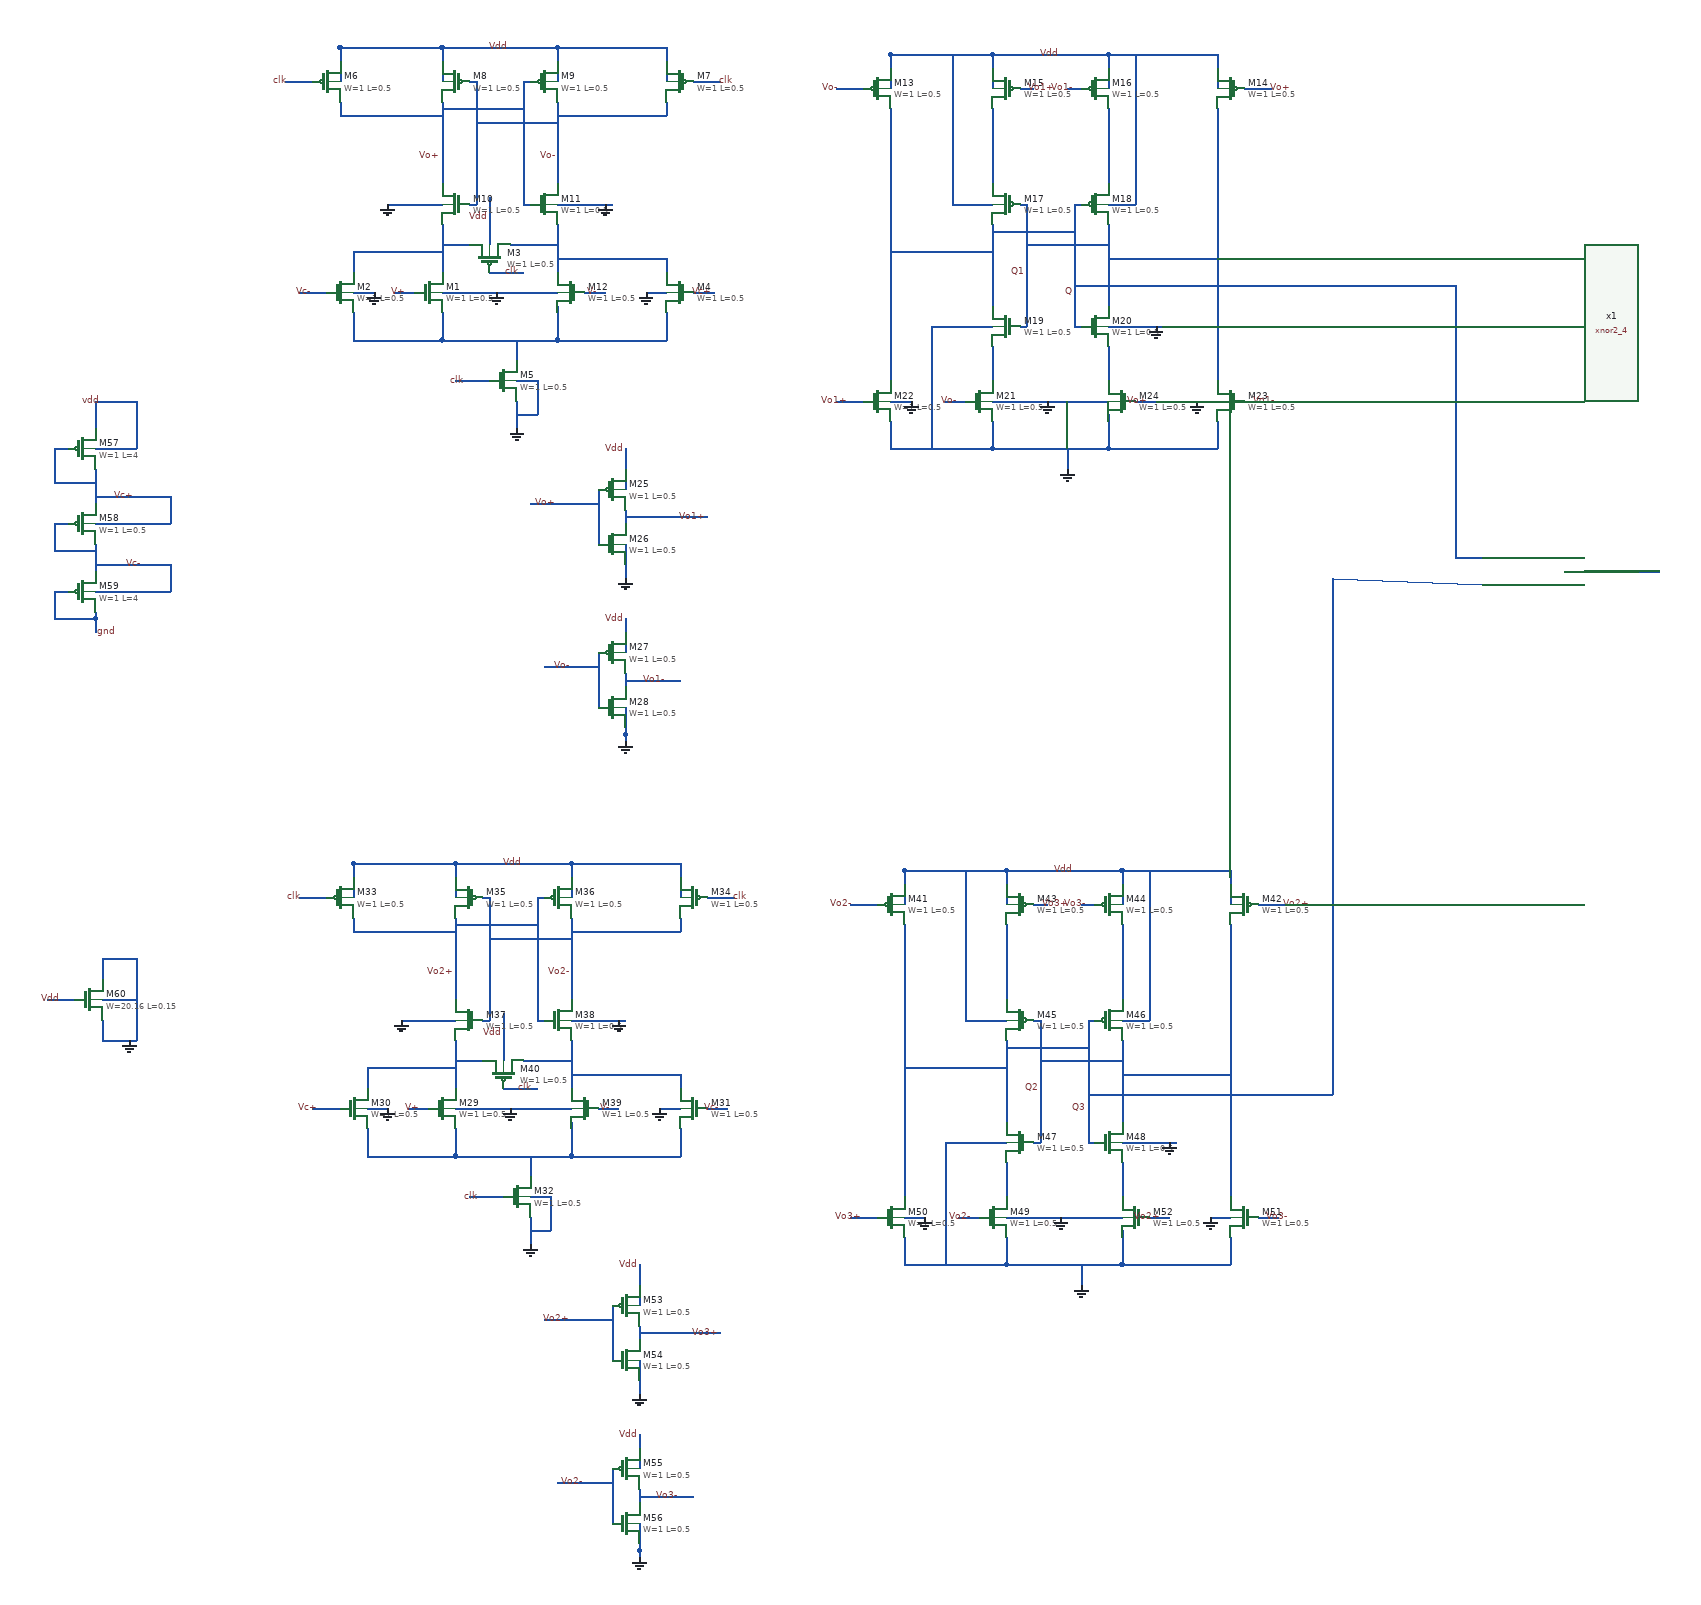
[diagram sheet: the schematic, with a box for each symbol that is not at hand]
v {xschem version=3.4.4 file_version=1.2
}
G {}
K {}
V {}
S {}
E {}
N -1410 -840 -1410 -720 {
lab=Vo+}
N -1240 -840 -1240 -730 {
lab=Vo-}
N -1240 -730 -1240 -720 {
lab=Vo-}
N -1410 -920 -1410 -900 {
lab=Vdd}
N -1410 -920 -1240 -920 {
lab=Vdd}
N -1240 -920 -1240 -900 {
lab=Vdd}
N -1370 -870 -1360 -870 {
lab=Vo-}
N -1360 -870 -1360 -690 {
lab=Vo-}
N -1370 -690 -1360 -690 {
lab=Vo-}
N -1290 -870 -1280 -870 {
lab=Vo+}
N -1290 -870 -1290 -690 {
lab=Vo+}
N -1290 -690 -1280 -690 {
lab=Vo+}
N -1560 -920 -1410 -920 {
lab=Vdd}
N -1560 -920 -1560 -900 {
lab=Vdd}
N -1240 -920 -1080 -920 {
lab=Vdd}
N -1080 -920 -1080 -900 {
lab=Vdd}
N -1560 -840 -1560 -820 {
lab=Vo+}
N -1560 -820 -1410 -820 {
lab=Vo+}
N -1080 -840 -1080 -820 {
lab=Vo-}
N -1240 -820 -1080 -820 {
lab=Vo-}
N -1410 -830 -1290 -830 {
lab=Vo+}
N -1360 -810 -1240 -810 {
lab=Vo-}
N -1410 -660 -1410 -590 {
lab=#net1}
N -1240 -660 -1240 -590 {
lab=#net2}
N -1410 -530 -1410 -490 {
lab=#net3}
N -1410 -490 -1240 -490 {
lab=#net3}
N -1240 -540 -1240 -490 {
lab=#net3}
N -1080 -530 -1080 -490 {
lab=#net3}
N -1240 -490 -1080 -490 {
lab=#net3}
N -1080 -610 -1080 -590 {
lab=#net2}
N -1240 -610 -1080 -610 {
lab=#net2}
N -1540 -530 -1540 -490 {
lab=#net3}
N -1540 -490 -1410 -490 {
lab=#net3}
N -1540 -620 -1540 -590 {
lab=#net1}
N -1540 -620 -1410 -620 {
lab=#net1}
N -1300 -490 -1300 -460 {
lab=#net3}
N -1390 -430 -1340 -430 {
lab=clk}
N -1300 -400 -1300 -360 {
lab=GND}
N -1410 -630 -1370 -630 {
lab=#net1}
N -1310 -630 -1240 -630 {
lab=#net2}
N -1620 -560 -1580 -560 {
lab=Vc-}
N -1480 -560 -1450 -560 {
lab=V+}
N -1200 -560 -1170 -560 {
lab=V-}
N -1040 -560 -1010 -560 {
lab=Vc+}
N -1040 -870 -1000 -870 {
lab=clk}
N -1640 -870 -1600 -870 {
lab=clk}
N -1410 -560 -1240 -560 {
lab=GND}
N -1110 -560 -1080 -560 {
lab=GND}
N -1540 -560 -1510 -560 {
lab=GND}
N -1560 -890 -1560 -870 {
lab=Vdd}
N -1410 -890 -1410 -870 {
lab=Vdd}
N -1240 -900 -1240 -880 {
lab=Vdd}
N -1240 -890 -1240 -870 {
lab=Vdd}
N -1080 -910 -1080 -870 {
lab=Vdd}
N -1410 -910 -1410 -870 {
lab=Vdd}
N -1560 -920 -1560 -870 {
lab=Vdd}
N -1240 -690 -1160 -690 {
lab=GND}
N -1490 -690 -1410 -690 {
lab=GND}
N -1340 -700 -1340 -630 {
lab=Vdd}
N -1340 -590 -1290 -590 {
lab=clk}
N -1300 -430 -1270 -430 {
lab=GND}
N -1270 -430 -1270 -380 {
lab=GND}
N -1300 -380 -1270 -380 {
lab=GND}
N -600 -910 -600 -890 {
lab=Vdd}
N -600 -910 -430 -910 {
lab=Vdd}
N -430 -910 -430 -890 {
lab=Vdd}
N -560 -860 -550 -860 {
lab=Vo1+}
N -480 -860 -470 -860 {
lab=Vo1-}
N -750 -910 -600 -910 {
lab=Vdd}
N -750 -910 -750 -890 {
lab=Vdd}
N -430 -910 -270 -910 {
lab=Vdd}
N -270 -910 -270 -890 {
lab=Vdd}
N -750 -830 -750 -810 {
lab=Q}
N -270 -830 -270 -810 {
lab=Q1}
N -230 -860 -190 -860 {
lab=Vo+}
N -830 -860 -790 -860 {
lab=Vo-}
N -750 -880 -750 -860 {
lab=Vdd}
N -600 -880 -600 -860 {
lab=Vdd}
N -430 -890 -430 -870 {
lab=Vdd}
N -430 -880 -430 -860 {
lab=Vdd}
N -270 -900 -270 -860 {
lab=Vdd}
N -600 -900 -600 -860 {
lab=Vdd}
N -750 -910 -750 -860 {
lab=Vdd}
N -430 -830 -430 -740 {
lab=#net4}
N -600 -660 -600 -540 {
lab=Q}
N -430 -660 -430 -550 {
lab=Q1}
N -430 -550 -430 -540 {
lab=Q1}
N -600 -740 -600 -720 {
lab=#net5}
N -430 -740 -430 -720 {
lab=#net4}
N -560 -690 -550 -690 {
lab=Q1}
N -550 -690 -550 -510 {
lab=Q1}
N -560 -510 -550 -510 {
lab=Q1}
N -480 -690 -470 -690 {
lab=Q}
N -480 -690 -480 -510 {
lab=Q}
N -480 -510 -470 -510 {
lab=Q}
N -600 -650 -480 -650 {
lab=Q}
N -550 -630 -430 -630 {
lab=Q1}
N -430 -510 -350 -510 {
lab=GND}
N -600 -830 -600 -740 {
lab=#net5}
N -600 -370 -600 -330 {
lab=GND}
N -600 -330 -430 -330 {
lab=GND}
N -430 -380 -430 -330 {
lab=GND}
N -270 -370 -270 -330 {
lab=GND}
N -430 -330 -270 -330 {
lab=GND}
N -270 -450 -270 -430 {
lab=Q1}
N -750 -370 -750 -330 {
lab=GND}
N -730 -330 -600 -330 {
lab=GND}
N -750 -460 -750 -430 {
lab=Q}
N -490 -330 -490 -300 {
lab=GND}
N -830 -400 -790 -400 {
lab=Vo1+}
N -670 -400 -640 -400 {
lab=Vo-}
N -390 -400 -360 -400 {
lab=Vo+}
N -230 -400 -200 -400 {
lab=Vo1-}
N -600 -400 -430 -400 {
lab=GND}
N -300 -400 -270 -400 {
lab=GND}
N -750 -400 -720 -400 {
lab=GND}
N -600 -480 -600 -430 {
lab=#net6}
N -430 -480 -430 -430 {
lab=#net7}
N -750 -810 -750 -460 {
lab=Q}
N -270 -810 -270 -460 {
lab=Q1}
N -270 -460 -270 -450 {
lab=Q1}
N -750 -330 -730 -330 {
lab=GND}
N -490 -860 -480 -860 {
lab=Vo1-}
N -550 -860 -540 -860 {
lab=Vo1+}
N -750 -620 -600 -620 {
lab=Q}
N -430 -610 -270 -610 {
lab=Q1}
N -1280 -250 -1200 -250 {
lab=Vo+}
N -1260 -10 -1180 -10 {
lab=Vo-}
N -1140 10 -1060 10 {
lab=Vo1-}
N -660 -690 -600 -690 {
lab=Vdd}
N -660 -910 -660 -690 {
lab=Vdd}
N -430 -690 -390 -690 {
lab=Vdd}
N -390 -910 -390 -690 {
lab=Vdd}
N -690 -510 -600 -510 {
lab=GND}
N -690 -510 -690 -330 {
lab=GND}
N -1140 -160 -1140 -140 {
lab=GND}
N -1180 -270 -1180 -190 {
lab=Vo+}
N -1200 -250 -1180 -250 {
lab=Vo+}
N -1140 -240 -1140 -220 {
lab=Vo1+}
N -1140 -230 -1020 -230 {
lab=Vo1+}
N -1140 -330 -1140 -300 {
lab=Vdd}
N -1140 -320 -1140 -270 {
lab=Vdd}
N -1140 -190 -1140 -150 {
lab=GND}
N -1180 -30 -1180 50 {
lab=Vo-}
N -1140 0 -1140 20 {
lab=Vo1-}
N -1140 90 -1140 100 {
lab=GND}
N -1140 80 -1140 90 {
lab=GND}
N -1140 50 -1140 90 {
lab=GND}
N -1140 -80 -1140 -60 {
lab=Vdd}
N -1140 -70 -1140 -30 {
lab=Vdd}
N -1390 360 -1390 480 {
lab=Vo2+}
N -1220 360 -1220 470 {
lab=Vo2-}
N -1220 470 -1220 480 {
lab=Vo2-}
N -1390 280 -1390 300 {
lab=Vdd}
N -1390 280 -1220 280 {
lab=Vdd}
N -1220 280 -1220 300 {
lab=Vdd}
N -1350 330 -1340 330 {
lab=Vo2-}
N -1340 330 -1340 510 {
lab=Vo2-}
N -1350 510 -1340 510 {
lab=Vo2-}
N -1270 330 -1260 330 {
lab=Vo2+}
N -1270 330 -1270 510 {
lab=Vo2+}
N -1270 510 -1260 510 {
lab=Vo2+}
N -1540 280 -1390 280 {
lab=Vdd}
N -1540 280 -1540 300 {
lab=Vdd}
N -1220 280 -1060 280 {
lab=Vdd}
N -1060 280 -1060 300 {
lab=Vdd}
N -1540 360 -1540 380 {
lab=Vo2+}
N -1540 380 -1390 380 {
lab=Vo2+}
N -1060 360 -1060 380 {
lab=Vo2-}
N -1220 380 -1060 380 {
lab=Vo2-}
N -1390 370 -1270 370 {
lab=Vo2+}
N -1340 390 -1220 390 {
lab=Vo2-}
N -1390 540 -1390 610 {
lab=#net8}
N -1220 540 -1220 610 {
lab=#net9}
N -1390 670 -1390 710 {
lab=#net10}
N -1390 710 -1220 710 {
lab=#net10}
N -1220 660 -1220 710 {
lab=#net10}
N -1060 670 -1060 710 {
lab=#net10}
N -1220 710 -1060 710 {
lab=#net10}
N -1060 590 -1060 610 {
lab=#net9}
N -1220 590 -1060 590 {
lab=#net9}
N -1520 670 -1520 710 {
lab=#net10}
N -1520 710 -1390 710 {
lab=#net10}
N -1520 580 -1520 610 {
lab=#net8}
N -1520 580 -1390 580 {
lab=#net8}
N -1280 710 -1280 740 {
lab=#net10}
N -1370 770 -1320 770 {
lab=clk}
N -1280 800 -1280 840 {
lab=GND}
N -1390 570 -1350 570 {
lab=#net8}
N -1290 570 -1220 570 {
lab=#net9}
N -1600 640 -1560 640 {
lab=Vc+}
N -1460 640 -1430 640 {
lab=V+}
N -1180 640 -1150 640 {
lab=V-}
N -1020 640 -990 640 {
lab=Vc-}
N -1020 330 -980 330 {
lab=clk}
N -1620 330 -1580 330 {
lab=clk}
N -1390 640 -1220 640 {
lab=GND}
N -1090 640 -1060 640 {
lab=GND}
N -1520 640 -1490 640 {
lab=GND}
N -1540 310 -1540 330 {
lab=Vdd}
N -1390 310 -1390 330 {
lab=Vdd}
N -1220 300 -1220 320 {
lab=Vdd}
N -1220 310 -1220 330 {
lab=Vdd}
N -1060 290 -1060 330 {
lab=Vdd}
N -1390 290 -1390 330 {
lab=Vdd}
N -1540 280 -1540 330 {
lab=Vdd}
N -1220 510 -1140 510 {
lab=GND}
N -1470 510 -1390 510 {
lab=GND}
N -1320 500 -1320 570 {
lab=Vdd}
N -1320 610 -1270 610 {
lab=clk}
N -1280 770 -1250 770 {
lab=GND}
N -1250 770 -1250 820 {
lab=GND}
N -1280 820 -1250 820 {
lab=GND}
N -580 290 -580 310 {
lab=Vdd}
N -580 290 -410 290 {
lab=Vdd}
N -410 290 -410 310 {
lab=Vdd}
N -540 340 -530 340 {
lab=Vo3+}
N -460 340 -450 340 {
lab=Vo3-}
N -730 290 -580 290 {
lab=Vdd}
N -730 290 -730 310 {
lab=Vdd}
N -410 290 -250 290 {
lab=Vdd}
N -250 290 -250 310 {
lab=Vdd}
N -730 370 -730 390 {
lab=Q3}
N -250 370 -250 390 {
lab=Q2}
N -210 340 -170 340 {
lab=Vo2+}
N -810 340 -770 340 {
lab=Vo2-}
N -730 320 -730 340 {
lab=Vdd}
N -580 320 -580 340 {
lab=Vdd}
N -410 310 -410 330 {
lab=Vdd}
N -410 320 -410 340 {
lab=Vdd}
N -250 300 -250 340 {
lab=Vdd}
N -580 300 -580 340 {
lab=Vdd}
N -730 290 -730 340 {
lab=Vdd}
N -410 370 -410 460 {
lab=#net11}
N -580 540 -580 660 {
lab=Q3}
N -410 540 -410 650 {
lab=Q2}
N -410 650 -410 660 {
lab=Q2}
N -580 460 -580 480 {
lab=#net12}
N -410 460 -410 480 {
lab=#net11}
N -540 510 -530 510 {
lab=Q2}
N -530 510 -530 690 {
lab=Q2}
N -540 690 -530 690 {
lab=Q2}
N -460 510 -450 510 {
lab=Q3}
N -460 510 -460 690 {
lab=Q3}
N -460 690 -450 690 {
lab=Q3}
N -580 550 -460 550 {
lab=Q3}
N -530 570 -410 570 {
lab=Q2}
N -410 690 -330 690 {
lab=GND}
N -580 370 -580 460 {
lab=#net12}
N -580 830 -580 870 {
lab=GND}
N -580 870 -410 870 {
lab=GND}
N -410 820 -410 870 {
lab=GND}
N -250 830 -250 870 {
lab=GND}
N -410 870 -250 870 {
lab=GND}
N -250 750 -250 770 {
lab=Q2}
N -730 830 -730 870 {
lab=GND}
N -710 870 -580 870 {
lab=GND}
N -730 740 -730 770 {
lab=Q3}
N -470 870 -470 900 {
lab=GND}
N -810 800 -770 800 {
lab=Vo3+}
N -650 800 -620 800 {
lab=Vo2-}
N -370 800 -340 800 {
lab=Vo2+}
N -210 800 -180 800 {
lab=Vo3-}
N -580 800 -410 800 {
lab=GND}
N -280 800 -250 800 {
lab=GND}
N -730 800 -700 800 {
lab=GND}
N -580 720 -580 770 {
lab=#net13}
N -410 720 -410 770 {
lab=#net14}
N -730 390 -730 740 {
lab=Q3}
N -250 390 -250 740 {
lab=Q2}
N -250 740 -250 750 {
lab=Q2}
N -730 870 -710 870 {
lab=GND}
N -470 340 -460 340 {
lab=Vo3-}
N -530 340 -520 340 {
lab=Vo3+}
N -730 580 -580 580 {
lab=Q3}
N -410 590 -250 590 {
lab=Q2}
N -1260 950 -1180 950 {
lab=Vo2+}
N -1240 1190 -1160 1190 {
lab=Vo2-}
N -1120 1210 -1040 1210 {
lab=Vo3-}
N -640 510 -580 510 {
lab=Vdd}
N -640 290 -640 510 {
lab=Vdd}
N -410 510 -370 510 {
lab=Vdd}
N -370 290 -370 510 {
lab=Vdd}
N -670 690 -580 690 {
lab=GND}
N -670 690 -670 870 {
lab=GND}
N -1120 1040 -1120 1060 {
lab=GND}
N -1160 930 -1160 1010 {
lab=Vo2+}
N -1180 950 -1160 950 {
lab=Vo2+}
N -1120 960 -1120 980 {
lab=Vo3+}
N -1120 970 -1000 970 {
lab=Vo3+}
N -1120 870 -1120 900 {
lab=Vdd}
N -1120 880 -1120 930 {
lab=Vdd}
N -1120 1010 -1120 1050 {
lab=GND}
N -1160 1170 -1160 1250 {
lab=Vo2-}
N -1120 1200 -1120 1220 {
lab=Vo3-}
N -1120 1290 -1120 1300 {
lab=GND}
N -1120 1280 -1120 1290 {
lab=GND}
N -1120 1250 -1120 1290 {
lab=GND}
N -1120 1120 -1120 1140 {
lab=Vdd}
N -1120 1130 -1120 1170 {
lab=Vdd}
N -480 -570 80 -570 {
lab=Q}
N 80 -570 80 -170 {
lab=Q}
N 80 -170 120 -170 {
lab=Q}
N -460 620 -100 620 {
lab=Q3}
N -100 -140 -100 620 {
lab=Q3}
N -100 -140 120 -130 {
lab=Q3}
N 240 -150 380 -150 {
lab=#net15}
N -1920 -190 -1920 -150 {
lab=Vc-}
N -1920 -270 -1920 -250 {
lab=Vc+}
N -1920 -220 -1900 -220 {
lab=Vc+}
N -1920 -260 -1900 -260 {
lab=Vc+}
N -1920 -120 -1890 -120 {
lab=Vc-}
N -1920 -160 -1890 -160 {
lab=Vc-}
N -1980 -220 -1960 -220 {
lab=Vc-}
N -1980 -120 -1960 -120 {
lab=gnd}
N -1980 -220 -1980 -180 {
lab=Vc-}
N -1980 -180 -1920 -180 {
lab=Vc-}
N -1980 -120 -1980 -80 {
lab=gnd}
N -1980 -80 -1920 -80 {
lab=gnd}
N -1920 -300 -1920 -270 {
lab=Vc+}
N -1890 -120 -1810 -120 {
lab=Vc-}
N -1900 -220 -1810 -220 {
lab=Vc+}
N -1810 -260 -1810 -220 {
lab=Vc+}
N -1900 -260 -1810 -260 {
lab=Vc+}
N -1810 -160 -1810 -120 {
lab=Vc-}
N -1920 -390 -1920 -360 {
lab=vdd}
N -1980 -330 -1960 -330 {
lab=Vc+}
N -1980 -330 -1980 -280 {
lab=Vc+}
N -1980 -280 -1920 -280 {
lab=Vc+}
N -1920 -330 -1860 -330 {
lab=vdd}
N -1860 -370 -1860 -330 {
lab=vdd}
N -1920 -80 -1920 -60 {
lab=gnd}
N -1860 -400 -1860 -370 {
lab=vdd}
N -1920 -400 -1860 -400 {
lab=vdd}
N -1920 -400 -1920 -390 {
lab=vdd}
N -1920 -90 -1920 -80 {
lab=gnd}
N -1890 -160 -1810 -160 {
lab=Vc-}
N -1990 480 -1950 480 {
lab=Vdd}
N -1910 420 -1910 450 {
lab=GND}
N -1910 420 -1860 420 {
lab=GND}
N -1860 420 -1860 540 {
lab=GND}
N -1910 540 -1860 540 {
lab=GND}
N -1910 510 -1910 540 {
lab=GND}
N -1910 480 -1860 480 {
lab=GND}
C {sky130_fd_pr/nfet_01v8.sym} -1430 -560 0 0 {name=M1
L=0.5
W=1
nf=1 
mult=1
ad="'int((nf+1)/2) * W/nf * 0.29'" 
pd="'2*int((nf+1)/2) * (W/nf + 0.29)'"
as="'int((nf+2)/2) * W/nf * 0.29'" 
ps="'2*int((nf+2)/2) * (W/nf + 0.29)'"
nrd="'0.29 / W'" nrs="'0.29 / W'"
sa=0 sb=0 sd=0
model=nfet_01v8
spiceprefix=X
}
C {sky130_fd_pr/nfet_01v8.sym} -1560 -560 0 0 {name=M2
L=0.5
W=1
nf=1 
mult=1
ad="'int((nf+1)/2) * W/nf * 0.29'" 
pd="'2*int((nf+1)/2) * (W/nf + 0.29)'"
as="'int((nf+2)/2) * W/nf * 0.29'" 
ps="'2*int((nf+2)/2) * (W/nf + 0.29)'"
nrd="'0.29 / W'" nrs="'0.29 / W'"
sa=0 sb=0 sd=0
model=nfet_01v8
spiceprefix=X
}
C {sky130_fd_pr/nfet_01v8.sym} -1060 -560 0 1 {name=M4
L=0.5
W=1
nf=1 
mult=1
ad="'int((nf+1)/2) * W/nf * 0.29'" 
pd="'2*int((nf+1)/2) * (W/nf + 0.29)'"
as="'int((nf+2)/2) * W/nf * 0.29'" 
ps="'2*int((nf+2)/2) * (W/nf + 0.29)'"
nrd="'0.29 / W'" nrs="'0.29 / W'"
sa=0 sb=0 sd=0
model=nfet_01v8
spiceprefix=X
}
C {sky130_fd_pr/nfet_01v8.sym} -1320 -430 0 0 {name=M5
L=0.5
W=1
nf=1 
mult=1
ad="'int((nf+1)/2) * W/nf * 0.29'" 
pd="'2*int((nf+1)/2) * (W/nf + 0.29)'"
as="'int((nf+2)/2) * W/nf * 0.29'" 
ps="'2*int((nf+2)/2) * (W/nf + 0.29)'"
nrd="'0.29 / W'" nrs="'0.29 / W'"
sa=0 sb=0 sd=0
model=nfet_01v8
spiceprefix=X
}
C {sky130_fd_pr/pfet_01v8.sym} -1580 -870 0 0 {name=M6
L=0.5
W=1
nf=1
mult=1
ad="'int((nf+1)/2) * W/nf * 0.29'" 
pd="'2*int((nf+1)/2) * (W/nf + 0.29)'"
as="'int((nf+2)/2) * W/nf * 0.29'" 
ps="'2*int((nf+2)/2) * (W/nf + 0.29)'"
nrd="'0.29 / W'" nrs="'0.29 / W'"
sa=0 sb=0 sd=0
model=pfet_01v8
spiceprefix=X
}
C {sky130_fd_pr/pfet_01v8.sym} -1060 -870 0 1 {name=M7
L=0.5
W=1
nf=1
mult=1
ad="'int((nf+1)/2) * W/nf * 0.29'" 
pd="'2*int((nf+1)/2) * (W/nf + 0.29)'"
as="'int((nf+2)/2) * W/nf * 0.29'" 
ps="'2*int((nf+2)/2) * (W/nf + 0.29)'"
nrd="'0.29 / W'" nrs="'0.29 / W'"
sa=0 sb=0 sd=0
model=pfet_01v8
spiceprefix=X
}
C {sky130_fd_pr/pfet_01v8.sym} -1390 -870 0 1 {name=M8
L=0.5
W=1
nf=1
mult=1
ad="'int((nf+1)/2) * W/nf * 0.29'" 
pd="'2*int((nf+1)/2) * (W/nf + 0.29)'"
as="'int((nf+2)/2) * W/nf * 0.29'" 
ps="'2*int((nf+2)/2) * (W/nf + 0.29)'"
nrd="'0.29 / W'" nrs="'0.29 / W'"
sa=0 sb=0 sd=0
model=pfet_01v8
spiceprefix=X
}
C {sky130_fd_pr/pfet_01v8.sym} -1260 -870 0 0 {name=M9
L=0.5
W=1
nf=1
mult=1
ad="'int((nf+1)/2) * W/nf * 0.29'" 
pd="'2*int((nf+1)/2) * (W/nf + 0.29)'"
as="'int((nf+2)/2) * W/nf * 0.29'" 
ps="'2*int((nf+2)/2) * (W/nf + 0.29)'"
nrd="'0.29 / W'" nrs="'0.29 / W'"
sa=0 sb=0 sd=0
model=pfet_01v8
spiceprefix=X
}
C {sky130_fd_pr/nfet_01v8.sym} -1390 -690 0 1 {name=M10
L=0.5
W=1
nf=1 
mult=1
ad="'int((nf+1)/2) * W/nf * 0.29'" 
pd="'2*int((nf+1)/2) * (W/nf + 0.29)'"
as="'int((nf+2)/2) * W/nf * 0.29'" 
ps="'2*int((nf+2)/2) * (W/nf + 0.29)'"
nrd="'0.29 / W'" nrs="'0.29 / W'"
sa=0 sb=0 sd=0
model=nfet_01v8
spiceprefix=X
}
C {sky130_fd_pr/nfet_01v8.sym} -1260 -690 0 0 {name=M11
L=0.5
W=1
nf=1 
mult=1
ad="'int((nf+1)/2) * W/nf * 0.29'" 
pd="'2*int((nf+1)/2) * (W/nf + 0.29)'"
as="'int((nf+2)/2) * W/nf * 0.29'" 
ps="'2*int((nf+2)/2) * (W/nf + 0.29)'"
nrd="'0.29 / W'" nrs="'0.29 / W'"
sa=0 sb=0 sd=0
model=nfet_01v8
spiceprefix=X
}
C {sky130_fd_pr/nfet_01v8.sym} -1220 -560 0 1 {name=M12
L=0.5
W=1
nf=1 
mult=1
ad="'int((nf+1)/2) * W/nf * 0.29'" 
pd="'2*int((nf+1)/2) * (W/nf + 0.29)'"
as="'int((nf+2)/2) * W/nf * 0.29'" 
ps="'2*int((nf+2)/2) * (W/nf + 0.29)'"
nrd="'0.29 / W'" nrs="'0.29 / W'"
sa=0 sb=0 sd=0
model=nfet_01v8
spiceprefix=X
}
C {devices/gnd.sym} -1300 -360 0 0 {name=l3 lab=GND}
C {devices/gnd.sym} -1510 -560 0 0 {name=l1 lab=GND}
C {devices/gnd.sym} -1330 -560 0 0 {name=l2 lab=GND}
C {devices/gnd.sym} -1110 -560 0 0 {name=l4 lab=GND}
C {devices/gnd.sym} -1170 -690 0 0 {name=l5 lab=GND}
C {devices/gnd.sym} -1490 -690 0 0 {name=l6 lab=GND}
C {devices/lab_wire.sym} -1310 -920 0 0 {name=p2 sig_type=std_logic lab=Vdd
}
C {sky130_fd_pr/pfet_01v8.sym} -1340 -610 1 1 {name=M3
L=0.5
W=1
nf=1
mult=1
ad="'int((nf+1)/2) * W/nf * 0.29'" 
pd="'2*int((nf+1)/2) * (W/nf + 0.29)'"
as="'int((nf+2)/2) * W/nf * 0.29'" 
ps="'2*int((nf+2)/2) * (W/nf + 0.29)'"
nrd="'0.29 / W'" nrs="'0.29 / W'"
sa=0 sb=0 sd=0
model=pfet_01v8
spiceprefix=X
}
C {devices/lab_wire.sym} -1340 -670 1 0 {name=p3 sig_type=std_logic lab=Vdd
}
C {devices/lab_wire.sym} -1010 -560 0 0 {name=p5 sig_type=std_logic lab=Vc+
}
C {devices/lab_wire.sym} -1600 -560 0 0 {name=p6 sig_type=std_logic lab=Vc-
}
C {devices/lab_wire.sym} -1460 -560 0 0 {name=p9 sig_type=std_logic lab=V+
}
C {devices/lab_wire.sym} -1180 -560 0 0 {name=p10 sig_type=std_logic lab=V-
}
C {devices/lab_pin.sym} -1375 -430 0 0 {name=p11 sig_type=std_logic lab=clk
}
C {devices/lab_pin.sym} -1295 -590 0 0 {name=p12 sig_type=std_logic lab=clk
}
C {devices/lab_pin.sym} -1635 -870 0 0 {name=p13 sig_type=std_logic lab=clk
}
C {devices/lab_pin.sym} -1005 -870 0 1 {name=p14 sig_type=std_logic lab=clk
}
C {devices/lab_wire.sym} -1410 -760 0 0 {name=p15 sig_type=std_logic lab=Vo+
}
C {devices/lab_wire.sym} -1240 -760 0 0 {name=p16 sig_type=std_logic lab=Vo-
}
C {sky130_fd_pr/pfet_01v8.sym} -770 -860 0 0 {name=M13
L=0.5
W=1
nf=1
mult=1
ad="'int((nf+1)/2) * W/nf * 0.29'" 
pd="'2*int((nf+1)/2) * (W/nf + 0.29)'"
as="'int((nf+2)/2) * W/nf * 0.29'" 
ps="'2*int((nf+2)/2) * (W/nf + 0.29)'"
nrd="'0.29 / W'" nrs="'0.29 / W'"
sa=0 sb=0 sd=0
model=pfet_01v8
spiceprefix=X
}
C {sky130_fd_pr/pfet_01v8.sym} -250 -860 0 1 {name=M14
L=0.5
W=1
nf=1
mult=1
ad="'int((nf+1)/2) * W/nf * 0.29'" 
pd="'2*int((nf+1)/2) * (W/nf + 0.29)'"
as="'int((nf+2)/2) * W/nf * 0.29'" 
ps="'2*int((nf+2)/2) * (W/nf + 0.29)'"
nrd="'0.29 / W'" nrs="'0.29 / W'"
sa=0 sb=0 sd=0
model=pfet_01v8
spiceprefix=X
}
C {sky130_fd_pr/pfet_01v8.sym} -580 -860 0 1 {name=M15
L=0.5
W=1
nf=1
mult=1
ad="'int((nf+1)/2) * W/nf * 0.29'" 
pd="'2*int((nf+1)/2) * (W/nf + 0.29)'"
as="'int((nf+2)/2) * W/nf * 0.29'" 
ps="'2*int((nf+2)/2) * (W/nf + 0.29)'"
nrd="'0.29 / W'" nrs="'0.29 / W'"
sa=0 sb=0 sd=0
model=pfet_01v8
spiceprefix=X
}
C {sky130_fd_pr/pfet_01v8.sym} -450 -860 0 0 {name=M16
L=0.5
W=1
nf=1
mult=1
ad="'int((nf+1)/2) * W/nf * 0.29'" 
pd="'2*int((nf+1)/2) * (W/nf + 0.29)'"
as="'int((nf+2)/2) * W/nf * 0.29'" 
ps="'2*int((nf+2)/2) * (W/nf + 0.29)'"
nrd="'0.29 / W'" nrs="'0.29 / W'"
sa=0 sb=0 sd=0
model=pfet_01v8
spiceprefix=X
}
C {devices/lab_wire.sym} -500 -910 0 0 {name=p17 sig_type=std_logic lab=Vdd
}
C {devices/lab_pin.sym} -825 -860 0 0 {name=p18 sig_type=std_logic lab=Vo-
}
C {devices/lab_pin.sym} -195 -860 0 1 {name=p19 sig_type=std_logic lab=Vo+
}
C {sky130_fd_pr/pfet_01v8.sym} -580 -690 0 1 {name=M17
L=0.5
W=1
nf=1
mult=1
ad="'int((nf+1)/2) * W/nf * 0.29'" 
pd="'2*int((nf+1)/2) * (W/nf + 0.29)'"
as="'int((nf+2)/2) * W/nf * 0.29'" 
ps="'2*int((nf+2)/2) * (W/nf + 0.29)'"
nrd="'0.29 / W'" nrs="'0.29 / W'"
sa=0 sb=0 sd=0
model=pfet_01v8
spiceprefix=X
}
C {sky130_fd_pr/pfet_01v8.sym} -450 -690 0 0 {name=M18
L=0.5
W=1
nf=1
mult=1
ad="'int((nf+1)/2) * W/nf * 0.29'" 
pd="'2*int((nf+1)/2) * (W/nf + 0.29)'"
as="'int((nf+2)/2) * W/nf * 0.29'" 
ps="'2*int((nf+2)/2) * (W/nf + 0.29)'"
nrd="'0.29 / W'" nrs="'0.29 / W'"
sa=0 sb=0 sd=0
model=pfet_01v8
spiceprefix=X
}
C {sky130_fd_pr/nfet_01v8.sym} -580 -510 0 1 {name=M19
L=0.5
W=1
nf=1 
mult=1
ad="'int((nf+1)/2) * W/nf * 0.29'" 
pd="'2*int((nf+1)/2) * (W/nf + 0.29)'"
as="'int((nf+2)/2) * W/nf * 0.29'" 
ps="'2*int((nf+2)/2) * (W/nf + 0.29)'"
nrd="'0.29 / W'" nrs="'0.29 / W'"
sa=0 sb=0 sd=0
model=nfet_01v8
spiceprefix=X
}
C {sky130_fd_pr/nfet_01v8.sym} -450 -510 0 0 {name=M20
L=0.5
W=1
nf=1 
mult=1
ad="'int((nf+1)/2) * W/nf * 0.29'" 
pd="'2*int((nf+1)/2) * (W/nf + 0.29)'"
as="'int((nf+2)/2) * W/nf * 0.29'" 
ps="'2*int((nf+2)/2) * (W/nf + 0.29)'"
nrd="'0.29 / W'" nrs="'0.29 / W'"
sa=0 sb=0 sd=0
model=nfet_01v8
spiceprefix=X
}
C {devices/gnd.sym} -360 -510 0 0 {name=l13 lab=GND}
C {sky130_fd_pr/nfet_01v8.sym} -620 -400 0 0 {name=M21
L=0.5
W=1
nf=1 
mult=1
ad="'int((nf+1)/2) * W/nf * 0.29'" 
pd="'2*int((nf+1)/2) * (W/nf + 0.29)'"
as="'int((nf+2)/2) * W/nf * 0.29'" 
ps="'2*int((nf+2)/2) * (W/nf + 0.29)'"
nrd="'0.29 / W'" nrs="'0.29 / W'"
sa=0 sb=0 sd=0
model=nfet_01v8
spiceprefix=X
}
C {sky130_fd_pr/nfet_01v8.sym} -770 -400 0 0 {name=M22
L=0.5
W=1
nf=1 
mult=1
ad="'int((nf+1)/2) * W/nf * 0.29'" 
pd="'2*int((nf+1)/2) * (W/nf + 0.29)'"
as="'int((nf+2)/2) * W/nf * 0.29'" 
ps="'2*int((nf+2)/2) * (W/nf + 0.29)'"
nrd="'0.29 / W'" nrs="'0.29 / W'"
sa=0 sb=0 sd=0
model=nfet_01v8
spiceprefix=X
}
C {sky130_fd_pr/nfet_01v8.sym} -250 -400 0 1 {name=M23
L=0.5
W=1
nf=1 
mult=1
ad="'int((nf+1)/2) * W/nf * 0.29'" 
pd="'2*int((nf+1)/2) * (W/nf + 0.29)'"
as="'int((nf+2)/2) * W/nf * 0.29'" 
ps="'2*int((nf+2)/2) * (W/nf + 0.29)'"
nrd="'0.29 / W'" nrs="'0.29 / W'"
sa=0 sb=0 sd=0
model=nfet_01v8
spiceprefix=X
}
C {sky130_fd_pr/nfet_01v8.sym} -410 -400 0 1 {name=M24
L=0.5
W=1
nf=1 
mult=1
ad="'int((nf+1)/2) * W/nf * 0.29'" 
pd="'2*int((nf+1)/2) * (W/nf + 0.29)'"
as="'int((nf+2)/2) * W/nf * 0.29'" 
ps="'2*int((nf+2)/2) * (W/nf + 0.29)'"
nrd="'0.29 / W'" nrs="'0.29 / W'"
sa=0 sb=0 sd=0
model=nfet_01v8
spiceprefix=X
}
C {devices/gnd.sym} -720 -400 0 0 {name=l14 lab=GND}
C {devices/gnd.sym} -520 -400 0 0 {name=l15 lab=GND}
C {devices/gnd.sym} -300 -400 0 0 {name=l16 lab=GND}
C {devices/lab_wire.sym} -650 -400 0 0 {name=p23 sig_type=std_logic lab=Vo-
}
C {devices/lab_wire.sym} -370 -400 0 0 {name=p28 sig_type=std_logic lab=Vo+

}
C {devices/gnd.sym} -490 -300 0 0 {name=l17 lab=GND}
C {devices/lab_wire.sym} -1240 -250 0 0 {name=p21 sig_type=std_logic lab=Vo+
}
C {devices/lab_wire.sym} -1220 -10 0 0 {name=p29 sig_type=std_logic lab=Vo-
}
C {devices/lab_wire.sym} -1020 -230 0 0 {name=p30 sig_type=std_logic lab=Vo1+
}
C {devices/lab_wire.sym} -1080 10 0 0 {name=p31 sig_type=std_logic lab=Vo1-
}
C {devices/lab_wire.sym} -550 -860 0 1 {name=p32 sig_type=std_logic lab=Vo1+
}
C {devices/lab_wire.sym} -480 -860 0 0 {name=p33 sig_type=std_logic lab=Vo1-
}
C {devices/lab_wire.sym} -810 -400 0 0 {name=p20 sig_type=std_logic lab=Vo1+
}
C {devices/lab_wire.sym} -220 -400 0 1 {name=p26 sig_type=std_logic lab=Vo1-
}
C {devices/lab_wire.sym} -550 -590 0 0 {name=p34 sig_type=std_logic lab=Q1
}
C {devices/lab_wire.sym} -480 -560 0 0 {name=p35 sig_type=std_logic lab=Q
}
C {devices/gnd.sym} -1140 -140 0 0 {name=l31 lab=GND}
C {devices/lab_wire.sym} -1140 -330 0 0 {name=p63 sig_type=std_logic lab=Vdd
}
C {sky130_fd_pr/pfet_01v8.sym} -1160 -270 0 0 {name=M25
L=0.5
W=1
nf=1
mult=1
ad="'int((nf+1)/2) * W/nf * 0.29'" 
pd="'2*int((nf+1)/2) * (W/nf + 0.29)'"
as="'int((nf+2)/2) * W/nf * 0.29'" 
ps="'2*int((nf+2)/2) * (W/nf + 0.29)'"
nrd="'0.29 / W'" nrs="'0.29 / W'"
sa=0 sb=0 sd=0
model=pfet_01v8
spiceprefix=X
}
C {sky130_fd_pr/nfet_01v8.sym} -1160 -190 0 0 {name=M26
L=0.5
W=1
nf=1 
mult=1
ad="'int((nf+1)/2) * W/nf * 0.29'" 
pd="'2*int((nf+1)/2) * (W/nf + 0.29)'"
as="'int((nf+2)/2) * W/nf * 0.29'" 
ps="'2*int((nf+2)/2) * (W/nf + 0.29)'"
nrd="'0.29 / W'" nrs="'0.29 / W'"
sa=0 sb=0 sd=0
model=nfet_01v8
spiceprefix=X
}
C {sky130_fd_pr/pfet_01v8.sym} -1160 -30 0 0 {name=M27
L=0.5
W=1
nf=1
mult=1
ad="'int((nf+1)/2) * W/nf * 0.29'" 
pd="'2*int((nf+1)/2) * (W/nf + 0.29)'"
as="'int((nf+2)/2) * W/nf * 0.29'" 
ps="'2*int((nf+2)/2) * (W/nf + 0.29)'"
nrd="'0.29 / W'" nrs="'0.29 / W'"
sa=0 sb=0 sd=0
model=pfet_01v8
spiceprefix=X
}
C {sky130_fd_pr/nfet_01v8.sym} -1160 50 0 0 {name=M28
L=0.5
W=1
nf=1 
mult=1
ad="'int((nf+1)/2) * W/nf * 0.29'" 
pd="'2*int((nf+1)/2) * (W/nf + 0.29)'"
as="'int((nf+2)/2) * W/nf * 0.29'" 
ps="'2*int((nf+2)/2) * (W/nf + 0.29)'"
nrd="'0.29 / W'" nrs="'0.29 / W'"
sa=0 sb=0 sd=0
model=nfet_01v8
spiceprefix=X
}
C {devices/gnd.sym} -1140 100 0 0 {name=l7 lab=GND}
C {devices/lab_wire.sym} -1140 -80 0 0 {name=p1 sig_type=std_logic lab=Vdd
}
C {sky130_fd_pr/nfet_01v8.sym} -1410 640 0 0 {name=M29
L=0.5
W=1
nf=1 
mult=1
ad="'int((nf+1)/2) * W/nf * 0.29'" 
pd="'2*int((nf+1)/2) * (W/nf + 0.29)'"
as="'int((nf+2)/2) * W/nf * 0.29'" 
ps="'2*int((nf+2)/2) * (W/nf + 0.29)'"
nrd="'0.29 / W'" nrs="'0.29 / W'"
sa=0 sb=0 sd=0
model=nfet_01v8
spiceprefix=X
}
C {sky130_fd_pr/nfet_01v8.sym} -1540 640 0 0 {name=M30
L=0.5
W=1
nf=1 
mult=1
ad="'int((nf+1)/2) * W/nf * 0.29'" 
pd="'2*int((nf+1)/2) * (W/nf + 0.29)'"
as="'int((nf+2)/2) * W/nf * 0.29'" 
ps="'2*int((nf+2)/2) * (W/nf + 0.29)'"
nrd="'0.29 / W'" nrs="'0.29 / W'"
sa=0 sb=0 sd=0
model=nfet_01v8
spiceprefix=X
}
C {sky130_fd_pr/nfet_01v8.sym} -1040 640 0 1 {name=M31
L=0.5
W=1
nf=1 
mult=1
ad="'int((nf+1)/2) * W/nf * 0.29'" 
pd="'2*int((nf+1)/2) * (W/nf + 0.29)'"
as="'int((nf+2)/2) * W/nf * 0.29'" 
ps="'2*int((nf+2)/2) * (W/nf + 0.29)'"
nrd="'0.29 / W'" nrs="'0.29 / W'"
sa=0 sb=0 sd=0
model=nfet_01v8
spiceprefix=X
}
C {sky130_fd_pr/nfet_01v8.sym} -1300 770 0 0 {name=M32
L=0.5
W=1
nf=1 
mult=1
ad="'int((nf+1)/2) * W/nf * 0.29'" 
pd="'2*int((nf+1)/2) * (W/nf + 0.29)'"
as="'int((nf+2)/2) * W/nf * 0.29'" 
ps="'2*int((nf+2)/2) * (W/nf + 0.29)'"
nrd="'0.29 / W'" nrs="'0.29 / W'"
sa=0 sb=0 sd=0
model=nfet_01v8
spiceprefix=X
}
C {sky130_fd_pr/pfet_01v8.sym} -1560 330 0 0 {name=M33
L=0.5
W=1
nf=1
mult=1
ad="'int((nf+1)/2) * W/nf * 0.29'" 
pd="'2*int((nf+1)/2) * (W/nf + 0.29)'"
as="'int((nf+2)/2) * W/nf * 0.29'" 
ps="'2*int((nf+2)/2) * (W/nf + 0.29)'"
nrd="'0.29 / W'" nrs="'0.29 / W'"
sa=0 sb=0 sd=0
model=pfet_01v8
spiceprefix=X
}
C {sky130_fd_pr/pfet_01v8.sym} -1040 330 0 1 {name=M34
L=0.5
W=1
nf=1
mult=1
ad="'int((nf+1)/2) * W/nf * 0.29'" 
pd="'2*int((nf+1)/2) * (W/nf + 0.29)'"
as="'int((nf+2)/2) * W/nf * 0.29'" 
ps="'2*int((nf+2)/2) * (W/nf + 0.29)'"
nrd="'0.29 / W'" nrs="'0.29 / W'"
sa=0 sb=0 sd=0
model=pfet_01v8
spiceprefix=X
}
C {sky130_fd_pr/pfet_01v8.sym} -1370 330 0 1 {name=M35
L=0.5
W=1
nf=1
mult=1
ad="'int((nf+1)/2) * W/nf * 0.29'" 
pd="'2*int((nf+1)/2) * (W/nf + 0.29)'"
as="'int((nf+2)/2) * W/nf * 0.29'" 
ps="'2*int((nf+2)/2) * (W/nf + 0.29)'"
nrd="'0.29 / W'" nrs="'0.29 / W'"
sa=0 sb=0 sd=0
model=pfet_01v8
spiceprefix=X
}
C {sky130_fd_pr/pfet_01v8.sym} -1240 330 0 0 {name=M36
L=0.5
W=1
nf=1
mult=1
ad="'int((nf+1)/2) * W/nf * 0.29'" 
pd="'2*int((nf+1)/2) * (W/nf + 0.29)'"
as="'int((nf+2)/2) * W/nf * 0.29'" 
ps="'2*int((nf+2)/2) * (W/nf + 0.29)'"
nrd="'0.29 / W'" nrs="'0.29 / W'"
sa=0 sb=0 sd=0
model=pfet_01v8
spiceprefix=X
}
C {sky130_fd_pr/nfet_01v8.sym} -1370 510 0 1 {name=M37
L=0.5
W=1
nf=1 
mult=1
ad="'int((nf+1)/2) * W/nf * 0.29'" 
pd="'2*int((nf+1)/2) * (W/nf + 0.29)'"
as="'int((nf+2)/2) * W/nf * 0.29'" 
ps="'2*int((nf+2)/2) * (W/nf + 0.29)'"
nrd="'0.29 / W'" nrs="'0.29 / W'"
sa=0 sb=0 sd=0
model=nfet_01v8
spiceprefix=X
}
C {sky130_fd_pr/nfet_01v8.sym} -1240 510 0 0 {name=M38
L=0.5
W=1
nf=1 
mult=1
ad="'int((nf+1)/2) * W/nf * 0.29'" 
pd="'2*int((nf+1)/2) * (W/nf + 0.29)'"
as="'int((nf+2)/2) * W/nf * 0.29'" 
ps="'2*int((nf+2)/2) * (W/nf + 0.29)'"
nrd="'0.29 / W'" nrs="'0.29 / W'"
sa=0 sb=0 sd=0
model=nfet_01v8
spiceprefix=X
}
C {sky130_fd_pr/nfet_01v8.sym} -1200 640 0 1 {name=M39
L=0.5
W=1
nf=1 
mult=1
ad="'int((nf+1)/2) * W/nf * 0.29'" 
pd="'2*int((nf+1)/2) * (W/nf + 0.29)'"
as="'int((nf+2)/2) * W/nf * 0.29'" 
ps="'2*int((nf+2)/2) * (W/nf + 0.29)'"
nrd="'0.29 / W'" nrs="'0.29 / W'"
sa=0 sb=0 sd=0
model=nfet_01v8
spiceprefix=X
}
C {devices/gnd.sym} -1280 840 0 0 {name=l8 lab=GND}
C {devices/gnd.sym} -1490 640 0 0 {name=l9 lab=GND}
C {devices/gnd.sym} -1310 640 0 0 {name=l10 lab=GND}
C {devices/gnd.sym} -1090 640 0 0 {name=l11 lab=GND}
C {devices/gnd.sym} -1150 510 0 0 {name=l12 lab=GND}
C {devices/gnd.sym} -1470 510 0 0 {name=l18 lab=GND}
C {devices/lab_wire.sym} -1290 280 0 0 {name=p4 sig_type=std_logic lab=Vdd
}
C {sky130_fd_pr/pfet_01v8.sym} -1320 590 1 1 {name=M40
L=0.5
W=1
nf=1
mult=1
ad="'int((nf+1)/2) * W/nf * 0.29'" 
pd="'2*int((nf+1)/2) * (W/nf + 0.29)'"
as="'int((nf+2)/2) * W/nf * 0.29'" 
ps="'2*int((nf+2)/2) * (W/nf + 0.29)'"
nrd="'0.29 / W'" nrs="'0.29 / W'"
sa=0 sb=0 sd=0
model=pfet_01v8
spiceprefix=X
}
C {devices/lab_wire.sym} -1320 530 1 0 {name=p7 sig_type=std_logic lab=Vdd
}
C {devices/lab_wire.sym} -1440 640 0 0 {name=p24 sig_type=std_logic lab=V+
}
C {devices/lab_wire.sym} -1160 640 0 0 {name=p25 sig_type=std_logic lab=V-
}
C {devices/lab_pin.sym} -1355 770 0 0 {name=p27 sig_type=std_logic lab=clk
}
C {devices/lab_pin.sym} -1275 610 0 0 {name=p36 sig_type=std_logic lab=clk
}
C {devices/lab_pin.sym} -1615 330 0 0 {name=p37 sig_type=std_logic lab=clk
}
C {devices/lab_pin.sym} -985 330 0 1 {name=p38 sig_type=std_logic lab=clk
}
C {devices/lab_wire.sym} -1390 440 0 0 {name=p39 sig_type=std_logic lab=Vo2+
}
C {devices/lab_wire.sym} -1220 440 0 0 {name=p40 sig_type=std_logic lab=Vo2-
}
C {sky130_fd_pr/pfet_01v8.sym} -750 340 0 0 {name=M41
L=0.5
W=1
nf=1
mult=1
ad="'int((nf+1)/2) * W/nf * 0.29'" 
pd="'2*int((nf+1)/2) * (W/nf + 0.29)'"
as="'int((nf+2)/2) * W/nf * 0.29'" 
ps="'2*int((nf+2)/2) * (W/nf + 0.29)'"
nrd="'0.29 / W'" nrs="'0.29 / W'"
sa=0 sb=0 sd=0
model=pfet_01v8
spiceprefix=X
}
C {sky130_fd_pr/pfet_01v8.sym} -230 340 0 1 {name=M42
L=0.5
W=1
nf=1
mult=1
ad="'int((nf+1)/2) * W/nf * 0.29'" 
pd="'2*int((nf+1)/2) * (W/nf + 0.29)'"
as="'int((nf+2)/2) * W/nf * 0.29'" 
ps="'2*int((nf+2)/2) * (W/nf + 0.29)'"
nrd="'0.29 / W'" nrs="'0.29 / W'"
sa=0 sb=0 sd=0
model=pfet_01v8
spiceprefix=X
}
C {sky130_fd_pr/pfet_01v8.sym} -560 340 0 1 {name=M43
L=0.5
W=1
nf=1
mult=1
ad="'int((nf+1)/2) * W/nf * 0.29'" 
pd="'2*int((nf+1)/2) * (W/nf + 0.29)'"
as="'int((nf+2)/2) * W/nf * 0.29'" 
ps="'2*int((nf+2)/2) * (W/nf + 0.29)'"
nrd="'0.29 / W'" nrs="'0.29 / W'"
sa=0 sb=0 sd=0
model=pfet_01v8
spiceprefix=X
}
C {sky130_fd_pr/pfet_01v8.sym} -430 340 0 0 {name=M44
L=0.5
W=1
nf=1
mult=1
ad="'int((nf+1)/2) * W/nf * 0.29'" 
pd="'2*int((nf+1)/2) * (W/nf + 0.29)'"
as="'int((nf+2)/2) * W/nf * 0.29'" 
ps="'2*int((nf+2)/2) * (W/nf + 0.29)'"
nrd="'0.29 / W'" nrs="'0.29 / W'"
sa=0 sb=0 sd=0
model=pfet_01v8
spiceprefix=X
}
C {devices/lab_wire.sym} -480 290 0 0 {name=p41 sig_type=std_logic lab=Vdd
}
C {devices/lab_pin.sym} -805 340 0 0 {name=p42 sig_type=std_logic lab=Vo2-
}
C {devices/lab_pin.sym} -175 340 0 1 {name=p43 sig_type=std_logic lab=Vo2+
}
C {sky130_fd_pr/pfet_01v8.sym} -560 510 0 1 {name=M45
L=0.5
W=1
nf=1
mult=1
ad="'int((nf+1)/2) * W/nf * 0.29'" 
pd="'2*int((nf+1)/2) * (W/nf + 0.29)'"
as="'int((nf+2)/2) * W/nf * 0.29'" 
ps="'2*int((nf+2)/2) * (W/nf + 0.29)'"
nrd="'0.29 / W'" nrs="'0.29 / W'"
sa=0 sb=0 sd=0
model=pfet_01v8
spiceprefix=X
}
C {sky130_fd_pr/pfet_01v8.sym} -430 510 0 0 {name=M46
L=0.5
W=1
nf=1
mult=1
ad="'int((nf+1)/2) * W/nf * 0.29'" 
pd="'2*int((nf+1)/2) * (W/nf + 0.29)'"
as="'int((nf+2)/2) * W/nf * 0.29'" 
ps="'2*int((nf+2)/2) * (W/nf + 0.29)'"
nrd="'0.29 / W'" nrs="'0.29 / W'"
sa=0 sb=0 sd=0
model=pfet_01v8
spiceprefix=X
}
C {sky130_fd_pr/nfet_01v8.sym} -560 690 0 1 {name=M47
L=0.5
W=1
nf=1 
mult=1
ad="'int((nf+1)/2) * W/nf * 0.29'" 
pd="'2*int((nf+1)/2) * (W/nf + 0.29)'"
as="'int((nf+2)/2) * W/nf * 0.29'" 
ps="'2*int((nf+2)/2) * (W/nf + 0.29)'"
nrd="'0.29 / W'" nrs="'0.29 / W'"
sa=0 sb=0 sd=0
model=nfet_01v8
spiceprefix=X
}
C {sky130_fd_pr/nfet_01v8.sym} -430 690 0 0 {name=M48
L=0.5
W=1
nf=1 
mult=1
ad="'int((nf+1)/2) * W/nf * 0.29'" 
pd="'2*int((nf+1)/2) * (W/nf + 0.29)'"
as="'int((nf+2)/2) * W/nf * 0.29'" 
ps="'2*int((nf+2)/2) * (W/nf + 0.29)'"
nrd="'0.29 / W'" nrs="'0.29 / W'"
sa=0 sb=0 sd=0
model=nfet_01v8
spiceprefix=X
}
C {devices/gnd.sym} -340 690 0 0 {name=l19 lab=GND}
C {sky130_fd_pr/nfet_01v8.sym} -600 800 0 0 {name=M49
L=0.5
W=1
nf=1 
mult=1
ad="'int((nf+1)/2) * W/nf * 0.29'" 
pd="'2*int((nf+1)/2) * (W/nf + 0.29)'"
as="'int((nf+2)/2) * W/nf * 0.29'" 
ps="'2*int((nf+2)/2) * (W/nf + 0.29)'"
nrd="'0.29 / W'" nrs="'0.29 / W'"
sa=0 sb=0 sd=0
model=nfet_01v8
spiceprefix=X
}
C {sky130_fd_pr/nfet_01v8.sym} -750 800 0 0 {name=M50
L=0.5
W=1
nf=1 
mult=1
ad="'int((nf+1)/2) * W/nf * 0.29'" 
pd="'2*int((nf+1)/2) * (W/nf + 0.29)'"
as="'int((nf+2)/2) * W/nf * 0.29'" 
ps="'2*int((nf+2)/2) * (W/nf + 0.29)'"
nrd="'0.29 / W'" nrs="'0.29 / W'"
sa=0 sb=0 sd=0
model=nfet_01v8
spiceprefix=X
}
C {sky130_fd_pr/nfet_01v8.sym} -230 800 0 1 {name=M51
L=0.5
W=1
nf=1 
mult=1
ad="'int((nf+1)/2) * W/nf * 0.29'" 
pd="'2*int((nf+1)/2) * (W/nf + 0.29)'"
as="'int((nf+2)/2) * W/nf * 0.29'" 
ps="'2*int((nf+2)/2) * (W/nf + 0.29)'"
nrd="'0.29 / W'" nrs="'0.29 / W'"
sa=0 sb=0 sd=0
model=nfet_01v8
spiceprefix=X
}
C {sky130_fd_pr/nfet_01v8.sym} -390 800 0 1 {name=M52
L=0.5
W=1
nf=1 
mult=1
ad="'int((nf+1)/2) * W/nf * 0.29'" 
pd="'2*int((nf+1)/2) * (W/nf + 0.29)'"
as="'int((nf+2)/2) * W/nf * 0.29'" 
ps="'2*int((nf+2)/2) * (W/nf + 0.29)'"
nrd="'0.29 / W'" nrs="'0.29 / W'"
sa=0 sb=0 sd=0
model=nfet_01v8
spiceprefix=X
lab=Vo2+}
C {devices/gnd.sym} -700 800 0 0 {name=l20 lab=GND}
C {devices/gnd.sym} -500 800 0 0 {name=l21 lab=GND}
C {devices/gnd.sym} -280 800 0 0 {name=l22 lab=GND}
C {devices/lab_wire.sym} -630 800 0 0 {name=p44 sig_type=std_logic lab=Vo2-
}
C {devices/lab_wire.sym} -350 800 0 0 {name=p45 sig_type=std_logic lab=Vo2+

}
C {devices/gnd.sym} -470 900 0 0 {name=l23 lab=GND}
C {devices/lab_wire.sym} -1220 950 0 0 {name=p46 sig_type=std_logic lab=Vo2+
}
C {devices/lab_wire.sym} -1200 1190 0 0 {name=p47 sig_type=std_logic lab=Vo2-
}
C {devices/lab_wire.sym} -1000 970 0 0 {name=p48 sig_type=std_logic lab=Vo3+
}
C {devices/lab_wire.sym} -1060 1210 0 0 {name=p49 sig_type=std_logic lab=Vo3-
}
C {devices/lab_wire.sym} -530 340 0 1 {name=p50 sig_type=std_logic lab=Vo3+
}
C {devices/lab_wire.sym} -460 340 0 0 {name=p51 sig_type=std_logic lab=Vo3-
}
C {devices/lab_wire.sym} -790 800 0 0 {name=p52 sig_type=std_logic lab=Vo3+
}
C {devices/lab_wire.sym} -200 800 0 1 {name=p53 sig_type=std_logic lab=Vo3-
}
C {devices/lab_wire.sym} -530 610 0 0 {name=p54 sig_type=std_logic lab=Q2
}
C {devices/lab_wire.sym} -460 640 0 0 {name=p55 sig_type=std_logic lab=Q3
}
C {devices/gnd.sym} -1120 1060 0 0 {name=l24 lab=GND}
C {devices/lab_wire.sym} -1120 870 0 0 {name=p56 sig_type=std_logic lab=Vdd
}
C {sky130_fd_pr/pfet_01v8.sym} -1140 930 0 0 {name=M53
L=0.5
W=1
nf=1
mult=1
ad="'int((nf+1)/2) * W/nf * 0.29'" 
pd="'2*int((nf+1)/2) * (W/nf + 0.29)'"
as="'int((nf+2)/2) * W/nf * 0.29'" 
ps="'2*int((nf+2)/2) * (W/nf + 0.29)'"
nrd="'0.29 / W'" nrs="'0.29 / W'"
sa=0 sb=0 sd=0
model=pfet_01v8
spiceprefix=X
}
C {sky130_fd_pr/nfet_01v8.sym} -1140 1010 0 0 {name=M54
L=0.5
W=1
nf=1 
mult=1
ad="'int((nf+1)/2) * W/nf * 0.29'" 
pd="'2*int((nf+1)/2) * (W/nf + 0.29)'"
as="'int((nf+2)/2) * W/nf * 0.29'" 
ps="'2*int((nf+2)/2) * (W/nf + 0.29)'"
nrd="'0.29 / W'" nrs="'0.29 / W'"
sa=0 sb=0 sd=0
model=nfet_01v8
spiceprefix=X
}
C {sky130_fd_pr/pfet_01v8.sym} -1140 1170 0 0 {name=M55
L=0.5
W=1
nf=1
mult=1
ad="'int((nf+1)/2) * W/nf * 0.29'" 
pd="'2*int((nf+1)/2) * (W/nf + 0.29)'"
as="'int((nf+2)/2) * W/nf * 0.29'" 
ps="'2*int((nf+2)/2) * (W/nf + 0.29)'"
nrd="'0.29 / W'" nrs="'0.29 / W'"
sa=0 sb=0 sd=0
model=pfet_01v8
spiceprefix=X
}
C {sky130_fd_pr/nfet_01v8.sym} -1140 1250 0 0 {name=M56
L=0.5
W=1
nf=1 
mult=1
ad="'int((nf+1)/2) * W/nf * 0.29'" 
pd="'2*int((nf+1)/2) * (W/nf + 0.29)'"
as="'int((nf+2)/2) * W/nf * 0.29'" 
ps="'2*int((nf+2)/2) * (W/nf + 0.29)'"
nrd="'0.29 / W'" nrs="'0.29 / W'"
sa=0 sb=0 sd=0
model=nfet_01v8
spiceprefix=X
}
C {devices/gnd.sym} -1120 1300 0 0 {name=l25 lab=GND}
C {devices/lab_wire.sym} -1120 1120 0 0 {name=p57 sig_type=std_logic lab=Vdd
}
C {devices/lab_wire.sym} -1000 640 0 0 {name=p58 sig_type=std_logic lab=Vc-
}
C {devices/lab_wire.sym} -1590 640 0 0 {name=p59 sig_type=std_logic lab=Vc+
}
C {sky130_stdcells/xnor2_4.sym} 180 -150 0 0 {name=x1 VGND=VGND VNB=VNB VPB=VPB VPWR=VPWR prefix=sky130_fd_sc_hd__ }
C {devices/lab_pin.sym} -1910 -400 1 0 {name=p8 sig_type=std_logic lab=vdd}
C {sky130_fd_pr/pfet_01v8_lvt.sym} -1940 -330 0 0 {name=M57
L=4
W=1
nf=1
mult=1
ad="'int((nf+1)/2) * W/nf * 0.29'" 
pd="'2*int((nf+1)/2) * (W/nf + 0.29)'"
as="'int((nf+2)/2) * W/nf * 0.29'" 
ps="'2*int((nf+2)/2) * (W/nf + 0.29)'"
nrd="'0.29 / W'" nrs="'0.29 / W'"
sa=0 sb=0 sd=0
model=pfet_01v8_lvt
spiceprefix=X
}
C {sky130_fd_pr/pfet_01v8_lvt.sym} -1940 -220 0 0 {name=M58
L=0.5
W=1
nf=1
mult=1
ad="'int((nf+1)/2) * W/nf * 0.29'" 
pd="'2*int((nf+1)/2) * (W/nf + 0.29)'"
as="'int((nf+2)/2) * W/nf * 0.29'" 
ps="'2*int((nf+2)/2) * (W/nf + 0.29)'"
nrd="'0.29 / W'" nrs="'0.29 / W'"
sa=0 sb=0 sd=0
model=pfet_01v8_lvt
spiceprefix=X
}
C {sky130_fd_pr/pfet_01v8_lvt.sym} -1940 -120 0 0 {name=M59
L=4
W=1
nf=1
mult=1
ad="'int((nf+1)/2) * W/nf * 0.29'" 
pd="'2*int((nf+1)/2) * (W/nf + 0.29)'"
as="'int((nf+2)/2) * W/nf * 0.29'" 
ps="'2*int((nf+2)/2) * (W/nf + 0.29)'"
nrd="'0.29 / W'" nrs="'0.29 / W'"
sa=0 sb=0 sd=0
model=pfet_01v8_lvt
spiceprefix=X
}
C {devices/lab_pin.sym} -1920 -60 2 0 {name=p61 sig_type=std_logic lab=gnd}
C {devices/lab_wire.sym} -1850 -160 0 0 {name=p22 sig_type=std_logic lab=Vc-
}
C {devices/lab_wire.sym} -1860 -260 0 0 {name=p60 sig_type=std_logic lab=Vc+
}
C {sky130_fd_pr/nfet_01v8.sym} -1930 480 0 0 {name=M60
L=0.15
W=20.16
nf=1 
mult=1
ad="'int((nf+1)/2) * W/nf * 0.29'" 
pd="'2*int((nf+1)/2) * (W/nf + 0.29)'"
as="'int((nf+2)/2) * W/nf * 0.29'" 
ps="'2*int((nf+2)/2) * (W/nf + 0.29)'"
nrd="'0.29 / W'" nrs="'0.29 / W'"
sa=0 sb=0 sd=0
model=nfet_01v8
spiceprefix=X
}
C {devices/lab_wire.sym} -1970 480 0 0 {name=p62 sig_type=std_logic lab=Vdd
}
C {devices/gnd.sym} -1870 540 0 0 {name=l26 lab=GND}
